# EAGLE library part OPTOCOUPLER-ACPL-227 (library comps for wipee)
Avago ACPL-227-50CE DC Input, Transistor Output Dual Optocoupler, SMT SOIC 8 2 channels, 50ma, 1.4v, delays 2us-3us Doc: http://docs-europe.electrocomponents.com/webdocs/0db7/0900766b80db7ce4.pdf Ref RS: 693-6797

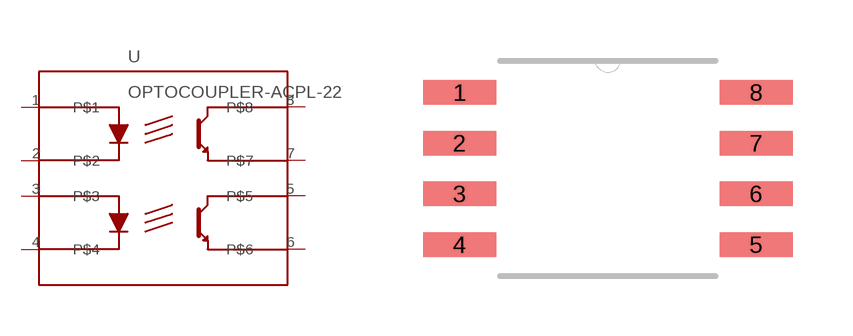
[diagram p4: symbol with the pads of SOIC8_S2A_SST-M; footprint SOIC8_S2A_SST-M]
Designator prefix -

## OPTOCOUPLER-ACPL-227  [SOIC8_S2A_SST-M]
1  P$1
2  P$2
3  P$3
4  P$4
5  P$5
6  P$6
7  P$7
8  P$8

## Footprint SOIC8_S2A_SST-M (pad centres in mm)
smd 1.829 x 0.61: 1 -3.708,1.905; 2 -3.708,0.635; 3 -3.708,-0.635; 4 -3.708,-1.905; 5 3.708,-1.905; 6 3.708,-0.635; 7 3.708,0.635; 8 3.708,1.905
